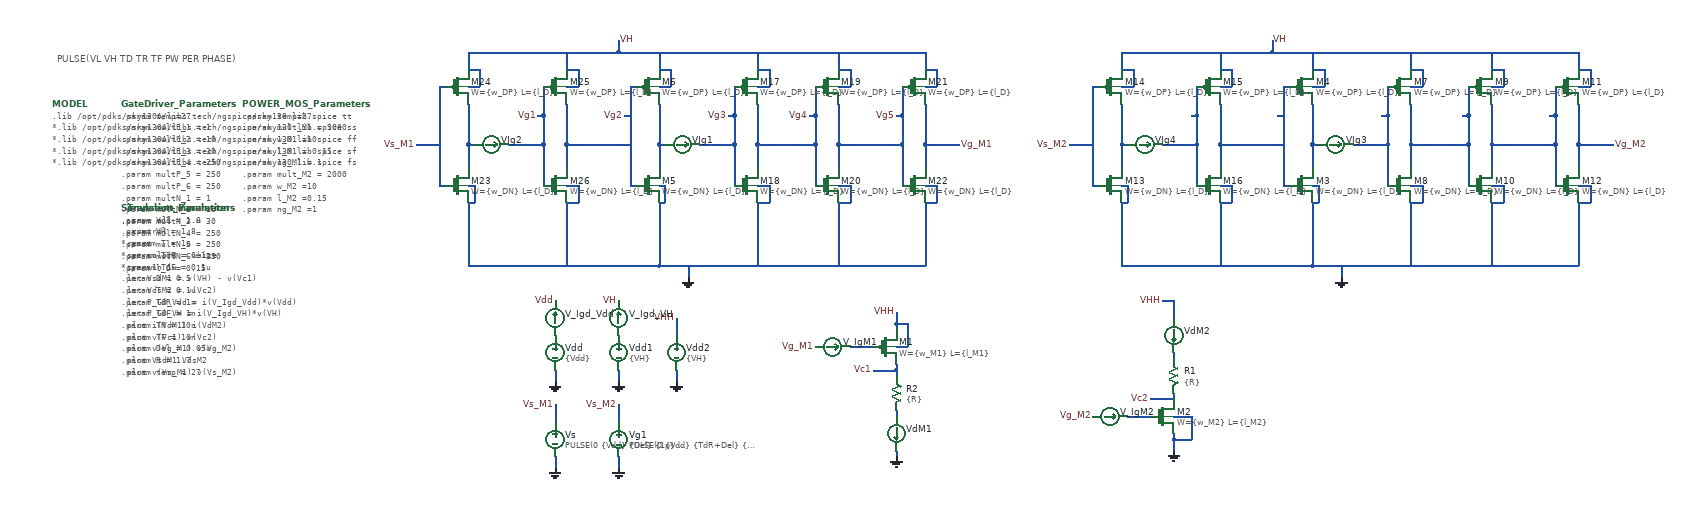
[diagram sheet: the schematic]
v {xschem version=3.4.5 file_version=1.2
}
G {}
K {}
V {}
S {}
E {}
T {PULSE(VL VH TD TR TF PW PER PHASE) 
} -1260 -1100 0 0 0.4 0.4 {}
N -400 -550 -400 -530 {
lab=GND}
N -400 -490 -400 -460 {
lab=Vs_M1}
N -400 -400 -400 -380 {
lab=GND}
N -290 -550 -290 -530 {
lab=GND}
N 250 -940 300 -940 {
lab=Vg_M1}
N 670 -470 700 -470 {
lab=GND}
N 110 -590 150 -590 {
lab=#net1}
N 190 -630 190 -620 {
lab=VHH}
N 190 -590 210 -590 {
lab=VHH}
N 210 -630 210 -590 {
lab=VHH}
N 190 -630 210 -630 {
lab=VHH}
N 590 -470 630 -470 {
lab=#net2}
N 700 -470 700 -430 {
lab=GND}
N 670 -430 700 -430 {
lab=GND}
N 670 -440 670 -430 {
lab=GND}
N 670 -430 670 -410 {
lab=GND}
N -290 -490 -290 -460 {
lab=Vs_M2}
N -290 -400 -290 -380 {
lab=GND}
N 670 -580 670 -570 {
lab=#net3}
N 670 -510 670 -500 {
lab=Vc2}
N 190 -480 190 -470 {
lab=#net4}
N 190 -550 190 -540 {
lab=Vc1}
N 190 -410 190 -400 {
lab=GND}
N 150 -550 190 -550 {
lab=Vc1}
N 190 -560 190 -550 {
lab=Vc1}
N 630 -500 670 -500 {
lab=Vc2}
N 670 -670 670 -640 {
lab=VHH}
N 190 -650 190 -630 {
lab=VHH}
N 650 -670 670 -670 {
lab=VHH}
N -190 -640 -190 -610 {
lab=VHH}
N -190 -550 -190 -530 {
lab=GND}
N -290 -1120 -290 -1100 {
lab=VH}
N 260 -940 270 -940 {
lab=Vg_M1}
N -220 -940 -220 -900 {
lab=#net5}
N 70 -730 240 -730 {
lab=GND}
N -100 -730 70 -730 {
lab=GND}
N -340 -940 -270 -940 {
lab=Vg2}
N -90 -940 -90 -870 {
lab=Vg3}
N -220 -1010 -220 -940 {
lab=#net5}
N -90 -990 -90 -940 {
lab=Vg3}
N -50 -940 -50 -900 {
lab=Vg4}
N 70 -1100 240 -1100 {
lab=VH}
N -100 -1100 70 -1100 {
lab=VH}
N -290 -1100 -100 -1100 {
lab=VH}
N -50 -940 -10 -940 {
lab=Vg4}
N -50 -1010 -50 -940 {
lab=Vg4}
N -220 -870 -210 -870 {
lab=GND}
N -210 -870 -210 -840 {
lab=GND}
N -220 -840 -210 -840 {
lab=GND}
N -50 -870 -30 -870 {
lab=GND}
N -30 -870 -30 -840 {
lab=GND}
N -50 -840 -30 -840 {
lab=GND}
N -220 -1040 -200 -1040 {
lab=VH}
N -200 -1070 -200 -1040 {
lab=VH}
N -220 -1070 -200 -1070 {
lab=VH}
N -50 -1040 -30 -1040 {
lab=VH}
N -30 -1070 -30 -1040 {
lab=VH}
N -50 -1070 -30 -1070 {
lab=VH}
N -150 -940 -90 -940 {
lab=Vg3}
N -220 -940 -210 -940 {
lab=#net5}
N -100 -990 -90 -990 {
lab=Vg3}
N -90 -1040 -90 -990 {
lab=Vg3}
N -270 -1040 -260 -1040 {
lab=Vg2}
N -270 -1040 -270 -870 {
lab=Vg2}
N -270 -870 -260 -870 {
lab=Vg2}
N -220 -840 -220 -730 {
lab=GND}
N -220 -730 -90 -730 {
lab=GND}
N -220 -1100 -220 -1070 {
lab=VH}
N -50 -1100 -50 -1070 {
lab=VH}
N -50 -840 -50 -730 {
lab=GND}
N 50 -940 50 -870 {
lab=Vg4}
N 50 -990 50 -940 {
lab=Vg4}
N 90 -940 90 -900 {
lab=Vg5}
N 90 -940 130 -940 {
lab=Vg5}
N 90 -1010 90 -940 {
lab=Vg5}
N 90 -870 110 -870 {
lab=GND}
N 110 -870 110 -840 {
lab=GND}
N 90 -840 110 -840 {
lab=GND}
N 90 -1040 110 -1040 {
lab=VH}
N 110 -1070 110 -1040 {
lab=VH}
N 90 -1070 110 -1070 {
lab=VH}
N -10 -940 50 -940 {
lab=Vg4}
N 40 -990 50 -990 {
lab=Vg4}
N 50 -1040 50 -990 {
lab=Vg4}
N 90 -1100 90 -1070 {
lab=VH}
N 90 -840 90 -730 {
lab=GND}
N 200 -940 200 -870 {
lab=Vg5}
N 200 -990 200 -940 {
lab=Vg5}
N 240 -940 240 -900 {
lab=Vg_M1}
N 240 -1010 240 -940 {
lab=Vg_M1}
N 240 -870 260 -870 {
lab=GND}
N 260 -870 260 -840 {
lab=GND}
N 240 -840 260 -840 {
lab=GND}
N 240 -1040 260 -1040 {
lab=VH}
N 260 -1070 260 -1040 {
lab=VH}
N 240 -1070 260 -1070 {
lab=VH}
N 140 -940 200 -940 {
lab=Vg5}
N 190 -990 200 -990 {
lab=Vg5}
N 200 -1040 200 -990 {
lab=Vg5}
N 240 -1100 240 -1070 {
lab=VH}
N 240 -840 240 -730 {
lab=GND}
N 130 -940 150 -940 {
lab=Vg5}
N 240 -940 270 -940 {
lab=Vg_M1}
N -550 -940 -550 -900 {
lab=#net6}
N -420 -940 -420 -870 {
lab=Vg1}
N -550 -1010 -550 -940 {
lab=#net6}
N -420 -990 -420 -940 {
lab=Vg1}
N -380 -940 -380 -900 {
lab=Vg2}
N -380 -940 -340 -940 {
lab=Vg2}
N -380 -1010 -380 -940 {
lab=Vg2}
N -550 -870 -540 -870 {
lab=GND}
N -540 -870 -540 -840 {
lab=GND}
N -550 -840 -540 -840 {
lab=GND}
N -380 -870 -360 -870 {
lab=GND}
N -360 -870 -360 -840 {
lab=GND}
N -380 -840 -360 -840 {
lab=GND}
N -550 -1040 -530 -1040 {
lab=VH}
N -530 -1070 -530 -1040 {
lab=VH}
N -550 -1070 -530 -1070 {
lab=VH}
N -380 -1040 -360 -1040 {
lab=VH}
N -360 -1070 -360 -1040 {
lab=VH}
N -380 -1070 -360 -1070 {
lab=VH}
N -480 -940 -420 -940 {
lab=Vg1}
N -550 -940 -540 -940 {
lab=#net6}
N -430 -990 -420 -990 {
lab=Vg1}
N -420 -1040 -420 -990 {
lab=Vg1}
N -600 -1040 -590 -1040 {
lab=Vs_M1}
N -600 -1040 -600 -870 {
lab=Vs_M1}
N -600 -870 -590 -870 {
lab=Vs_M1}
N -550 -730 -220 -730 {
lab=GND}
N -550 -840 -550 -730 {
lab=GND}
N -380 -840 -380 -730 {
lab=GND}
N -640 -940 -600 -940 {
lab=Vs_M1}
N -550 -1100 -290 -1100 {
lab=VH}
N -550 -1100 -550 -1070 {
lab=VH}
N -380 -1100 -380 -1070 {
lab=VH}
N -280 -990 -270 -990 {
lab=Vg2}
N -170 -730 -170 -710 {
lab=GND}
N 1380 -940 1430 -940 {
lab=Vg_M2}
N 840 -1120 840 -1100 {
lab=VH}
N 1390 -940 1400 -940 {
lab=Vg_M2}
N 910 -940 910 -900 {
lab=#net7}
N 1200 -730 1370 -730 {
lab=GND}
N 1030 -730 1200 -730 {
lab=GND}
N 790 -940 860 -940 {
lab=#net8}
N 1040 -940 1040 -870 {
lab=#net9}
N 910 -1010 910 -940 {
lab=#net7}
N 1040 -990 1040 -940 {
lab=#net9}
N 1080 -940 1080 -900 {
lab=#net10}
N 1200 -1100 1370 -1100 {
lab=VH}
N 1030 -1100 1200 -1100 {
lab=VH}
N 840 -1100 1030 -1100 {
lab=VH}
N 1080 -940 1120 -940 {
lab=#net10}
N 1080 -1010 1080 -940 {
lab=#net10}
N 910 -870 920 -870 {
lab=GND}
N 920 -870 920 -840 {
lab=GND}
N 910 -840 920 -840 {
lab=GND}
N 1080 -870 1100 -870 {
lab=GND}
N 1100 -870 1100 -840 {
lab=GND}
N 1080 -840 1100 -840 {
lab=GND}
N 910 -1040 930 -1040 {
lab=VH}
N 930 -1070 930 -1040 {
lab=VH}
N 910 -1070 930 -1070 {
lab=VH}
N 1080 -1040 1100 -1040 {
lab=VH}
N 1100 -1070 1100 -1040 {
lab=VH}
N 1080 -1070 1100 -1070 {
lab=VH}
N 980 -940 1040 -940 {
lab=#net9}
N 910 -940 920 -940 {
lab=#net7}
N 1030 -990 1040 -990 {
lab=#net9}
N 1040 -1040 1040 -990 {
lab=#net9}
N 860 -1040 870 -1040 {
lab=#net8}
N 860 -1040 860 -870 {
lab=#net8}
N 860 -870 870 -870 {
lab=#net8}
N 910 -840 910 -730 {
lab=GND}
N 910 -730 1040 -730 {
lab=GND}
N 910 -1100 910 -1070 {
lab=VH}
N 1080 -1100 1080 -1070 {
lab=VH}
N 1080 -840 1080 -730 {
lab=GND}
N 1180 -940 1180 -870 {
lab=#net10}
N 1180 -990 1180 -940 {
lab=#net10}
N 1220 -940 1220 -900 {
lab=#net11}
N 1220 -940 1260 -940 {
lab=#net11}
N 1220 -1010 1220 -940 {
lab=#net11}
N 1220 -870 1240 -870 {
lab=GND}
N 1240 -870 1240 -840 {
lab=GND}
N 1220 -840 1240 -840 {
lab=GND}
N 1220 -1040 1240 -1040 {
lab=VH}
N 1240 -1070 1240 -1040 {
lab=VH}
N 1220 -1070 1240 -1070 {
lab=VH}
N 1120 -940 1180 -940 {
lab=#net10}
N 1170 -990 1180 -990 {
lab=#net10}
N 1180 -1040 1180 -990 {
lab=#net10}
N 1220 -1100 1220 -1070 {
lab=VH}
N 1220 -840 1220 -730 {
lab=GND}
N 1330 -940 1330 -870 {
lab=#net11}
N 1330 -990 1330 -940 {
lab=#net11}
N 1370 -940 1370 -900 {
lab=Vg_M2}
N 1370 -1010 1370 -940 {
lab=Vg_M2}
N 1370 -870 1390 -870 {
lab=GND}
N 1390 -870 1390 -840 {
lab=GND}
N 1370 -840 1390 -840 {
lab=GND}
N 1370 -1040 1390 -1040 {
lab=VH}
N 1390 -1070 1390 -1040 {
lab=VH}
N 1370 -1070 1390 -1070 {
lab=VH}
N 1270 -940 1330 -940 {
lab=#net11}
N 1320 -990 1330 -990 {
lab=#net11}
N 1330 -1040 1330 -990 {
lab=#net11}
N 1370 -1100 1370 -1070 {
lab=VH}
N 1370 -840 1370 -730 {
lab=GND}
N 1260 -940 1280 -940 {
lab=#net11}
N 1370 -940 1400 -940 {
lab=Vg_M2}
N 580 -940 580 -900 {
lab=#net12}
N 710 -940 710 -870 {
lab=#net13}
N 580 -1010 580 -940 {
lab=#net12}
N 710 -990 710 -940 {
lab=#net13}
N 750 -940 750 -900 {
lab=#net8}
N 750 -940 790 -940 {
lab=#net8}
N 750 -1010 750 -940 {
lab=#net8}
N 580 -870 590 -870 {
lab=GND}
N 590 -870 590 -840 {
lab=GND}
N 580 -840 590 -840 {
lab=GND}
N 750 -870 770 -870 {
lab=GND}
N 770 -870 770 -840 {
lab=GND}
N 750 -840 770 -840 {
lab=GND}
N 580 -1040 600 -1040 {
lab=VH}
N 600 -1070 600 -1040 {
lab=VH}
N 580 -1070 600 -1070 {
lab=VH}
N 750 -1040 770 -1040 {
lab=VH}
N 770 -1070 770 -1040 {
lab=VH}
N 750 -1070 770 -1070 {
lab=VH}
N 650 -940 710 -940 {
lab=#net13}
N 580 -940 590 -940 {
lab=#net12}
N 700 -990 710 -990 {
lab=#net13}
N 710 -1040 710 -990 {
lab=#net13}
N 530 -1040 540 -1040 {
lab=Vs_M2}
N 530 -1040 530 -870 {
lab=Vs_M2}
N 530 -870 540 -870 {
lab=Vs_M2}
N 580 -730 910 -730 {
lab=GND}
N 580 -840 580 -730 {
lab=GND}
N 750 -840 750 -730 {
lab=GND}
N 490 -940 530 -940 {
lab=Vs_M2}
N 580 -1100 840 -1100 {
lab=VH}
N 580 -1100 580 -1070 {
lab=VH}
N 750 -1100 750 -1070 {
lab=VH}
N 850 -990 860 -990 {
lab=#net8}
N 960 -730 960 -710 {
lab=GND}
C {vsource.sym} -400 -580 0 0 {name=Vdd value=\{Vdd\} savecurrent=false}
C {lab_pin.sym} -400 -670 0 0 {name=p5 sig_type=std_logic lab=Vdd}
C {gnd.sym} -400 -530 0 0 {name=l2 lab=GND}
C {lab_pin.sym} -400 -490 0 0 {name=p4 sig_type=std_logic lab=Vs_M1}
C {vsource.sym} -400 -430 0 1 {name=Vs value="PULSE(0 \{Vdd\} \{Del\} \{1p\} \{1p\} \{T*D\} \{T\} 0)" savecurrent=false}
C {gnd.sym} -400 -380 0 0 {name=l5 lab=GND}
C {code.sym} -1150 -830 0 1 {name=Simulation_Parameters only_toplevel=false 

value="
.param Vdd = 1.8
.param VH = 1.8

*.param T = 1u
*.param TdR = 0.1u
*.param TdF = 0.1u

.param D = 0.5
.param T = 0.1u
.param TdR = 1n
.param TdF = 1n
.param TR = 10n
.param TF = 10n
.param Del = 0.05u

.param R = 1.7

.param temp = 27


"}
C {devices/code.sym} -1140 -830 0 0 {name=Transient_simulation only_toplevel=false 

value="
.save all
.control
reset
set color0 = white
tran 1n 1u

let VsdM1 = v(VH) - v(Vc1)
let VdsM2 = v(Vc2)
let P_GD_Vdd = i(V_Igd_Vdd)*v(Vdd)
let P_GD_VH = i(V_Igd_VH)*v(VH)

plot i(VdM1) i(VdM2)
plot v(Vc1) v(Vc2)
plot v(Vg_M1) v(Vg_M2)
plot VsdM1 VdsM2
plot v(Vs_M1) v(Vs_M2)
plot i(V_IgM1) i(V_IgM2)


meas tran P_GD_Vdd_mean AVG P_GD_Vdd from=0.5u to=1u
meas tran P_GD_VH_mean AVG P_GD_VH from=0.5u to=1u

let P_GD = P_GD_Vdd_mean + P_GD_VH_mean

meas TRAN td_off_M1 TRIG v(Vg_M1) VAL=0.18 RISE=1 TARG VsdM1 VAL=0.18 RISE=1
meas TRAN td_on_M1 TRIG v(Vg_M1) VAL=1.62 FALL=1 TARG VsdM1 VAL=1.62 FALL=1
meas TRAN td_on_M2 TRIG v(Vg_M2) VAL=0.18 RISE=1 TARG VdsM2 VAL=1.62 FALL=1
meas TRAN td_off_M2 TRIG v(Vg_M2) VAL=1.62 FALL=1 TARG VdsM2 VAL=0.18 RISE=1

meas TRAN tPdR1 TRIG v(Vs_M1) VAL=0.12 RISE=1 TARG v(Vg_M1) VAL=0.33 RISE=1
meas TRAN tPdF1 TRIG v(Vs_M1) VAL=1.08 FALL=1 TARG v(Vg_M1) VAL=2.97 FALL=1
*meas TRAN tPdR1 TRIG v(Vg_M2) VAL=2.97 FALL=1 TARG VdsM2 VAL=0.33 RISE=1
*meas TRAN tPdR1 TRIG v(Vg_M2) VAL=2.97 FALL=1 TARG VdsM2 VAL=0.33 RISE=1
let TdR = td_off_M1 - td_on_M2 
let TdF = td_on_M1 - td_off_M2
print TdR TdF P_GD


.endc

.end
"}
C {vsource.sym} -290 -580 0 0 {name=Vdd1 value=\{VH\} savecurrent=false}
C {lab_pin.sym} -290 -670 0 0 {name=p1 sig_type=std_logic lab=VH
value=\{VH\}}
C {gnd.sym} -290 -530 0 0 {name=l1 lab=GND
value=\{VH\}}
C {lab_pin.sym} -640 -940 0 0 {name=p2 sig_type=std_logic lab=Vs_M1}
C {lab_pin.sym} 300 -940 0 1 {name=p7 sig_type=std_logic lab=Vg_M1}
C {gnd.sym} 670 -410 0 0 {name=l4 lab=GND}
C {lab_pin.sym} 530 -470 0 0 {name=p8 sig_type=std_logic lab=Vg_M2}
C {lab_pin.sym} 50 -590 0 0 {name=p9 sig_type=std_logic lab=Vg_M1}
C {gnd.sym} 190 -400 0 0 {name=l7 lab=GND}
C {ammeter.sym} 670 -610 0 0 {name=VdM2 savecurrent=true spice_ignore=0}
C {ammeter.sym} 190 -440 0 0 {name=VdM1 savecurrent=true spice_ignore=0}
C {vsource.sym} -290 -430 0 0 {name=Vg1 value="PULSE(0 \{Vdd\} \{TdR+Del\} \{1p\} \{1p\} \{T*D-TdR-TdF\} \{T\} 0)" savecurrent=false}
C {gnd.sym} -290 -380 0 0 {name=l8 lab=GND}
C {lab_pin.sym} -290 -490 0 0 {name=p14 sig_type=std_logic lab=Vs_M2}
C {res.sym} 670 -540 0 0 {name=R1
value=\{R\}
footprint=1206
device=resistor
m=1}
C {res.sym} 190 -510 0 0 {name=R2
value=\{R\}
footprint=1206
device=resistor
m=1}
C {lab_pin.sym} 630 -500 0 0 {name=p15 sig_type=std_logic lab=Vc2}
C {lab_pin.sym} 150 -550 0 0 {name=p16 sig_type=std_logic lab=Vc1}
C {lab_pin.sym} 490 -940 0 0 {name=p10 sig_type=std_logic lab=Vs_M2}
C {ammeter.sym} 80 -590 3 0 {name=V_IgM1 savecurrent=true spice_ignore=0}
C {ammeter.sym} 560 -470 3 0 {name=V_IgM2 savecurrent=true spice_ignore=0}
C {lab_pin.sym} 190 -650 0 0 {name=p11 sig_type=std_logic lab=VHH
value=\{VH\}}
C {lab_pin.sym} 650 -670 0 0 {name=p12 sig_type=std_logic lab=VHH
value=\{VH\}}
C {vsource.sym} -190 -580 0 0 {name=Vdd2 value=\{VH\} savecurrent=false}
C {lab_pin.sym} -190 -640 0 0 {name=p19 sig_type=std_logic lab=VHH
value=\{VHH\}}
C {gnd.sym} -190 -530 0 0 {name=l9 lab=GND
value=\{VH\}}
C {ammeter.sym} -400 -640 2 0 {name=V_Igd_Vdd savecurrent=true spice_ignore=0}
C {ammeter.sym} -290 -640 2 0 {name=V_Igd_VH savecurrent=true spice_ignore=0}
C {sky130_fd_pr/pfet_01v8.sym} 170 -590 0 0 {name=M1
W=\{w_M1\}
L=\{l_M1\}
nf=\{ng_M1\}
mult=\{mult_M1\}
ad="'int((nf+1)/2) * W/nf * 0.29'" 
pd="'2*int((nf+1)/2) * (W/nf + 0.29)'"
as="'int((nf+2)/2) * W/nf * 0.29'" 
ps="'2*int((nf+2)/2) * (W/nf + 0.29)'"
nrd="'0.29 / W'" nrs="'0.29 / W'"
sa=0 sb=0 sd=0
model=pfet_01v8
spiceprefix=X
}
C {sky130_fd_pr/nfet_01v8.sym} 650 -470 0 0 {name=M2
W=\{w_M2\}
L=\{l_M2\}
nf=\{ng_M2\}
mult=\{mult_M2\}
ad="'int((nf+1)/2) * W/nf * 0.29'" 
pd="'2*int((nf+1)/2) * (W/nf + 0.29)'"
as="'int((nf+2)/2) * W/nf * 0.29'" 
ps="'2*int((nf+2)/2) * (W/nf + 0.29)'"
nrd="'0.29 / W'" nrs="'0.29 / W'"
sa=0 sb=0 sd=0
model=nfet_01v8
spiceprefix=X
}
C {code.sym} -940 -1010 0 0 {name=POWER_MOS_Parameters only_toplevel=false 

value="
.param temp=27
.param mult_M1 = 9000
.param w_M1 =10
.param l_M1 = 0.15
.param ng_M1 = 1

.param mult_M2 = 2000
.param w_M2 =10
.param l_M2 =0.15
.param ng_M2 =1



"}
C {code.sym} -1270 -1010 0 0 {name=MODEL only_toplevel=true spice_ignore=false
format="tcleval( @value )"
value="
.lib /opt/pdks/sky130A/libs.tech/ngspice/sky130.lib.spice tt
*.lib /opt/pdks/sky130A/libs.tech/ngspice/sky130.lib.spice ss
*.lib /opt/pdks/sky130A/libs.tech/ngspice/sky130.lib.spice ff
*.lib /opt/pdks/sky130A/libs.tech/ngspice/sky130.lib.spice sf
*.lib /opt/pdks/sky130A/libs.tech/ngspice/sky130.lib.spice fs
"}
C {lab_pin.sym} -290 -1120 0 1 {name=p20 sig_type=std_logic lab=VH
value=\{VH\}}
C {lab_pin.sym} -100 -990 0 0 {name=p22 sig_type=std_logic lab=Vg3}
C {ammeter.sym} -180 -940 3 0 {name=VIg1 savecurrent=true spice_ignore=0}
C {sky130_fd_pr/nfet_01v8.sym} -240 -870 0 0 {name=M5
W=\{w_DN\}
L=\{l_D\}
nf=1
mult=\{multP_3\}
ad="'int((nf+1)/2) * W/nf * 0.29'" 
pd="'2*int((nf+1)/2) * (W/nf + 0.29)'"
as="'int((nf+2)/2) * W/nf * 0.29'" 
ps="'2*int((nf+2)/2) * (W/nf + 0.29)'"
nrd="'0.29 / W'" nrs="'0.29 / W'"
sa=0 sb=0 sd=0
model=nfet_01v8
spiceprefix=X
}
C {sky130_fd_pr/pfet_01v8.sym} -240 -1040 0 0 {name=M6
W=\{w_DP\}
L=\{l_D\}
nf=1
mult=\{multP_3*3\}
ad="'int((nf+1)/2) * W/nf * 0.29'" 
pd="'2*int((nf+1)/2) * (W/nf + 0.29)'"
as="'int((nf+2)/2) * W/nf * 0.29'" 
ps="'2*int((nf+2)/2) * (W/nf + 0.29)'"
nrd="'0.29 / W'" nrs="'0.29 / W'"
sa=0 sb=0 sd=0
model=pfet_01v8
spiceprefix=X
}
C {sky130_fd_pr/pfet_01v8.sym} -70 -1040 0 0 {name=M17
W=\{w_DP\}
L=\{l_D\}
nf=1
mult=\{multP_4*3\}
ad="'int((nf+1)/2) * W/nf * 0.29'" 
pd="'2*int((nf+1)/2) * (W/nf + 0.29)'"
as="'int((nf+2)/2) * W/nf * 0.29'" 
ps="'2*int((nf+2)/2) * (W/nf + 0.29)'"
nrd="'0.29 / W'" nrs="'0.29 / W'"
sa=0 sb=0 sd=0
model=pfet_01v8
spiceprefix=X
}
C {sky130_fd_pr/nfet_01v8.sym} -70 -870 0 0 {name=M18
W=\{w_DN\}
L=\{l_D\}
nf=1
mult=\{multP_4\}
ad="'int((nf+1)/2) * W/nf * 0.29'" 
pd="'2*int((nf+1)/2) * (W/nf + 0.29)'"
as="'int((nf+2)/2) * W/nf * 0.29'" 
ps="'2*int((nf+2)/2) * (W/nf + 0.29)'"
nrd="'0.29 / W'" nrs="'0.29 / W'"
sa=0 sb=0 sd=0
model=nfet_01v8
spiceprefix=X
}
C {lab_pin.sym} 40 -990 0 0 {name=p23 sig_type=std_logic lab=Vg4}
C {sky130_fd_pr/pfet_01v8.sym} 70 -1040 0 0 {name=M19
W=\{w_DP\}
L=\{l_D\}
nf=1
mult=\{multP_5*3\}
ad="'int((nf+1)/2) * W/nf * 0.29'" 
pd="'2*int((nf+1)/2) * (W/nf + 0.29)'"
as="'int((nf+2)/2) * W/nf * 0.29'" 
ps="'2*int((nf+2)/2) * (W/nf + 0.29)'"
nrd="'0.29 / W'" nrs="'0.29 / W'"
sa=0 sb=0 sd=0
model=pfet_01v8
spiceprefix=X
}
C {sky130_fd_pr/nfet_01v8.sym} 70 -870 0 0 {name=M20
W=\{w_DN\}
L=\{l_D\}
nf=1
mult=\{multP_5\}
ad="'int((nf+1)/2) * W/nf * 0.29'" 
pd="'2*int((nf+1)/2) * (W/nf + 0.29)'"
as="'int((nf+2)/2) * W/nf * 0.29'" 
ps="'2*int((nf+2)/2) * (W/nf + 0.29)'"
nrd="'0.29 / W'" nrs="'0.29 / W'"
sa=0 sb=0 sd=0
model=nfet_01v8
spiceprefix=X
}
C {lab_pin.sym} 190 -990 0 0 {name=p24 sig_type=std_logic lab=Vg5}
C {sky130_fd_pr/pfet_01v8.sym} 220 -1040 0 0 {name=M21
W=\{w_DP\}
L=\{l_D\}
nf=1
mult=\{multP_6*3\}
ad="'int((nf+1)/2) * W/nf * 0.29'" 
pd="'2*int((nf+1)/2) * (W/nf + 0.29)'"
as="'int((nf+2)/2) * W/nf * 0.29'" 
ps="'2*int((nf+2)/2) * (W/nf + 0.29)'"
nrd="'0.29 / W'" nrs="'0.29 / W'"
sa=0 sb=0 sd=0
model=pfet_01v8
spiceprefix=X
}
C {sky130_fd_pr/nfet_01v8.sym} 220 -870 0 0 {name=M22
W=\{w_DN\}
L=\{l_D\}
nf=1
mult=\{multP_6\}
ad="'int((nf+1)/2) * W/nf * 0.29'" 
pd="'2*int((nf+1)/2) * (W/nf + 0.29)'"
as="'int((nf+2)/2) * W/nf * 0.29'" 
ps="'2*int((nf+2)/2) * (W/nf + 0.29)'"
nrd="'0.29 / W'" nrs="'0.29 / W'"
sa=0 sb=0 sd=0
model=nfet_01v8
spiceprefix=X
}
C {gnd.sym} -170 -710 0 0 {name=l10 lab=GND
value=\{VH\}}
C {lab_pin.sym} -430 -990 0 0 {name=p25 sig_type=std_logic lab=Vg1}
C {ammeter.sym} -510 -940 3 0 {name=VIg2 savecurrent=true spice_ignore=0}
C {sky130_fd_pr/nfet_01v8.sym} -570 -870 0 0 {name=M23
W=\{w_DN\}
L=\{l_D\}
nf=1
mult=\{multP_1\}
ad="'int((nf+1)/2) * W/nf * 0.29'" 
pd="'2*int((nf+1)/2) * (W/nf + 0.29)'"
as="'int((nf+2)/2) * W/nf * 0.29'" 
ps="'2*int((nf+2)/2) * (W/nf + 0.29)'"
nrd="'0.29 / W'" nrs="'0.29 / W'"
sa=0 sb=0 sd=0
model=nfet_01v8
spiceprefix=X
}
C {sky130_fd_pr/pfet_01v8.sym} -570 -1040 0 0 {name=M24
W=\{w_DP\}
L=\{l_D\}
nf=1
mult=\{multP_1*3\}
ad="'int((nf+1)/2) * W/nf * 0.29'" 
pd="'2*int((nf+1)/2) * (W/nf + 0.29)'"
as="'int((nf+2)/2) * W/nf * 0.29'" 
ps="'2*int((nf+2)/2) * (W/nf + 0.29)'"
nrd="'0.29 / W'" nrs="'0.29 / W'"
sa=0 sb=0 sd=0
model=pfet_01v8
spiceprefix=X
}
C {sky130_fd_pr/pfet_01v8.sym} -400 -1040 0 0 {name=M25
W=\{w_DP\}
L=\{l_D\}
nf=1
mult=\{multP_2*3\}
ad="'int((nf+1)/2) * W/nf * 0.29'" 
pd="'2*int((nf+1)/2) * (W/nf + 0.29)'"
as="'int((nf+2)/2) * W/nf * 0.29'" 
ps="'2*int((nf+2)/2) * (W/nf + 0.29)'"
nrd="'0.29 / W'" nrs="'0.29 / W'"
sa=0 sb=0 sd=0
model=pfet_01v8
spiceprefix=X
}
C {sky130_fd_pr/nfet_01v8.sym} -400 -870 0 0 {name=M26
W=\{w_DN\}
L=\{l_D\}
nf=1
mult=\{multP_2\}
ad="'int((nf+1)/2) * W/nf * 0.29'" 
pd="'2*int((nf+1)/2) * (W/nf + 0.29)'"
as="'int((nf+2)/2) * W/nf * 0.29'" 
ps="'2*int((nf+2)/2) * (W/nf + 0.29)'"
nrd="'0.29 / W'" nrs="'0.29 / W'"
sa=0 sb=0 sd=0
model=nfet_01v8
spiceprefix=X
}
C {lab_pin.sym} -280 -990 0 0 {name=p27 sig_type=std_logic lab=Vg2}
C {lab_pin.sym} 1430 -940 0 1 {name=p6 sig_type=std_logic lab=Vg_M2}
C {lab_pin.sym} 840 -1120 0 1 {name=p21 sig_type=std_logic lab=VH
value=\{VH\}}
C {ammeter.sym} 950 -940 3 0 {name=VIg3 savecurrent=true spice_ignore=0}
C {sky130_fd_pr/nfet_01v8.sym} 890 -870 0 0 {name=M3
W=\{w_DN\}
L=\{l_D\}
nf=1
mult=\{multN_3\}
ad="'int((nf+1)/2) * W/nf * 0.29'" 
pd="'2*int((nf+1)/2) * (W/nf + 0.29)'"
as="'int((nf+2)/2) * W/nf * 0.29'" 
ps="'2*int((nf+2)/2) * (W/nf + 0.29)'"
nrd="'0.29 / W'" nrs="'0.29 / W'"
sa=0 sb=0 sd=0
model=nfet_01v8
spiceprefix=X
}
C {sky130_fd_pr/pfet_01v8.sym} 890 -1040 0 0 {name=M4
W=\{w_DP\}
L=\{l_D\}
nf=1
mult=\{multN_3*3\}
ad="'int((nf+1)/2) * W/nf * 0.29'" 
pd="'2*int((nf+1)/2) * (W/nf + 0.29)'"
as="'int((nf+2)/2) * W/nf * 0.29'" 
ps="'2*int((nf+2)/2) * (W/nf + 0.29)'"
nrd="'0.29 / W'" nrs="'0.29 / W'"
sa=0 sb=0 sd=0
model=pfet_01v8
spiceprefix=X
}
C {sky130_fd_pr/pfet_01v8.sym} 1060 -1040 0 0 {name=M7
W=\{w_DP\}
L=\{l_D\}
nf=1
mult=\{multN_4*3\}
ad="'int((nf+1)/2) * W/nf * 0.29'" 
pd="'2*int((nf+1)/2) * (W/nf + 0.29)'"
as="'int((nf+2)/2) * W/nf * 0.29'" 
ps="'2*int((nf+2)/2) * (W/nf + 0.29)'"
nrd="'0.29 / W'" nrs="'0.29 / W'"
sa=0 sb=0 sd=0
model=pfet_01v8
spiceprefix=X
}
C {sky130_fd_pr/nfet_01v8.sym} 1060 -870 0 0 {name=M8
W=\{w_DN\}
L=\{l_D\}
nf=1
mult=\{multN_4\}
ad="'int((nf+1)/2) * W/nf * 0.29'" 
pd="'2*int((nf+1)/2) * (W/nf + 0.29)'"
as="'int((nf+2)/2) * W/nf * 0.29'" 
ps="'2*int((nf+2)/2) * (W/nf + 0.29)'"
nrd="'0.29 / W'" nrs="'0.29 / W'"
sa=0 sb=0 sd=0
model=nfet_01v8
spiceprefix=X
}
C {sky130_fd_pr/pfet_01v8.sym} 1200 -1040 0 0 {name=M9
W=\{w_DP\}
L=\{l_D\}
nf=1
mult=\{multN_5*3\}
ad="'int((nf+1)/2) * W/nf * 0.29'" 
pd="'2*int((nf+1)/2) * (W/nf + 0.29)'"
as="'int((nf+2)/2) * W/nf * 0.29'" 
ps="'2*int((nf+2)/2) * (W/nf + 0.29)'"
nrd="'0.29 / W'" nrs="'0.29 / W'"
sa=0 sb=0 sd=0
model=pfet_01v8
spiceprefix=X
}
C {sky130_fd_pr/nfet_01v8.sym} 1200 -870 0 0 {name=M10
W=\{w_DN\}
L=\{l_D\}
nf=1
mult=\{multN_5\}
ad="'int((nf+1)/2) * W/nf * 0.29'" 
pd="'2*int((nf+1)/2) * (W/nf + 0.29)'"
as="'int((nf+2)/2) * W/nf * 0.29'" 
ps="'2*int((nf+2)/2) * (W/nf + 0.29)'"
nrd="'0.29 / W'" nrs="'0.29 / W'"
sa=0 sb=0 sd=0
model=nfet_01v8
spiceprefix=X
}
C {sky130_fd_pr/pfet_01v8.sym} 1350 -1040 0 0 {name=M11
W=\{w_DP\}
L=\{l_D\}
nf=1
mult=\{multN_6*3\}
ad="'int((nf+1)/2) * W/nf * 0.29'" 
pd="'2*int((nf+1)/2) * (W/nf + 0.29)'"
as="'int((nf+2)/2) * W/nf * 0.29'" 
ps="'2*int((nf+2)/2) * (W/nf + 0.29)'"
nrd="'0.29 / W'" nrs="'0.29 / W'"
sa=0 sb=0 sd=0
model=pfet_01v8
spiceprefix=X
}
C {sky130_fd_pr/nfet_01v8.sym} 1350 -870 0 0 {name=M12
W=\{w_DN\}
L=\{l_D\}
nf=1
mult=\{multN_6\}
ad="'int((nf+1)/2) * W/nf * 0.29'" 
pd="'2*int((nf+1)/2) * (W/nf + 0.29)'"
as="'int((nf+2)/2) * W/nf * 0.29'" 
ps="'2*int((nf+2)/2) * (W/nf + 0.29)'"
nrd="'0.29 / W'" nrs="'0.29 / W'"
sa=0 sb=0 sd=0
model=nfet_01v8
spiceprefix=X
}
C {gnd.sym} 960 -710 0 0 {name=l6 lab=GND
value=\{VH\}}
C {ammeter.sym} 620 -940 3 0 {name=VIg4 savecurrent=true spice_ignore=0}
C {sky130_fd_pr/nfet_01v8.sym} 560 -870 0 0 {name=M13
W=\{w_DN\}
L=\{l_D\}
nf=1
mult=\{multN_1\}
ad="'int((nf+1)/2) * W/nf * 0.29'" 
pd="'2*int((nf+1)/2) * (W/nf + 0.29)'"
as="'int((nf+2)/2) * W/nf * 0.29'" 
ps="'2*int((nf+2)/2) * (W/nf + 0.29)'"
nrd="'0.29 / W'" nrs="'0.29 / W'"
sa=0 sb=0 sd=0
model=nfet_01v8
spiceprefix=X
}
C {sky130_fd_pr/pfet_01v8.sym} 560 -1040 0 0 {name=M14
W=\{w_DP\}
L=\{l_D\}
nf=1
mult=\{multN_1*3\}
ad="'int((nf+1)/2) * W/nf * 0.29'" 
pd="'2*int((nf+1)/2) * (W/nf + 0.29)'"
as="'int((nf+2)/2) * W/nf * 0.29'" 
ps="'2*int((nf+2)/2) * (W/nf + 0.29)'"
nrd="'0.29 / W'" nrs="'0.29 / W'"
sa=0 sb=0 sd=0
model=pfet_01v8
spiceprefix=X
}
C {sky130_fd_pr/pfet_01v8.sym} 730 -1040 0 0 {name=M15
W=\{w_DP\}
L=\{l_D\}
nf=1
mult=\{multN_2*3\}
ad="'int((nf+1)/2) * W/nf * 0.29'" 
pd="'2*int((nf+1)/2) * (W/nf + 0.29)'"
as="'int((nf+2)/2) * W/nf * 0.29'" 
ps="'2*int((nf+2)/2) * (W/nf + 0.29)'"
nrd="'0.29 / W'" nrs="'0.29 / W'"
sa=0 sb=0 sd=0
model=pfet_01v8
spiceprefix=X
}
C {sky130_fd_pr/nfet_01v8.sym} 730 -870 0 0 {name=M16
W=\{w_DN\}
L=\{l_D\}
nf=1
mult=\{multN_2\}
ad="'int((nf+1)/2) * W/nf * 0.29'" 
pd="'2*int((nf+1)/2) * (W/nf + 0.29)'"
as="'int((nf+2)/2) * W/nf * 0.29'" 
ps="'2*int((nf+2)/2) * (W/nf + 0.29)'"
nrd="'0.29 / W'" nrs="'0.29 / W'"
sa=0 sb=0 sd=0
model=nfet_01v8
spiceprefix=X
}
C {code.sym} -1150 -1010 0 0 {name=GateDriver_Parameters only_toplevel=false 

value="
.param temp=27

.param multP_1 = 1
.param multP_2 = 10
.param multP_3 = 30
.param multP_4 = 250
.param multP_5 = 250
.param multP_6 = 250

.param multN_1 = 1
.param multN_2 = 10
.param multN_3 = 30
.param multN_4 = 250
.param multN_5 = 250
.param multN_6 = 250

.param l_D = 0.15
.param w_DN = 0.42
.param w_DP = 0.42



"}
